VERSION 5.8 ;
BUSBITCHARS "[]" ;
DIVIDERCHAR "/" ;
UNITS
    DATABASE MICRONS 1000 ;
END UNITS

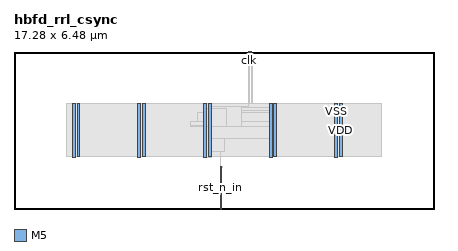
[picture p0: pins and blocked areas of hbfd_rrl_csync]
MACRO hbfd_rrl_csync
  FOREIGN hbfd_rrl_csync 0 0 ;
  CLASS BLOCK ;
  SIZE 17.28 BY 6.48 ;
  PIN clk
    DIRECTION INPUT ;
    USE SIGNAL ;
    PORT
      LAYER M5 ;
        RECT  9.648 6.396 9.672 6.48 ;
    END
  END clk
  PIN rst_n
    DIRECTION OUTPUT ;
    USE SIGNAL ;
    PORT
      LAYER M5 ;
        RECT  9.744 6.396 9.768 6.48 ;
    END
  END rst_n
  PIN rst_n_in
    DIRECTION INPUT ;
    USE SIGNAL ;
    PORT
      LAYER M5 ;
        RECT  8.496 0 8.52 0.084 ;
    END
    PORT
      LAYER M5 ;
        RECT  8.496 0.016 8.52 1.763 ;
    END
  END rst_n_in
  PIN VDD
    DIRECTION INOUT ;
    USE POWER ;
    PORT
      LAYER M5 ;
        RECT  13.392 2.151 13.512 4.329 ;
        RECT  10.692 2.151 10.812 4.329 ;
        RECT  7.992 2.151 8.112 4.329 ;
        RECT  5.292 2.151 5.412 4.329 ;
        RECT  2.592 2.151 2.712 4.329 ;
    END
  END VDD
  PIN VSS
    DIRECTION INOUT ;
    USE GROUND ;
    PORT
      LAYER M5 ;
        RECT  13.2 2.137 13.32 4.343 ;
        RECT  10.5 2.137 10.62 4.343 ;
        RECT  7.8 2.137 7.92 4.343 ;
        RECT  5.1 2.137 5.22 4.343 ;
        RECT  2.4 2.137 2.52 4.343 ;
    END
  END VSS
  # OT_OBS_CLOSED layer=M5 d_um=1.536 added=0
  OBS
    LAYER RVTN ;
     RECT  2.16 2.16 15.12 2.295 ;
     RECT  2.16 2.565 15.12 2.835 ;
     RECT  2.16 3.105 15.12 3.375 ;
     RECT  2.16 3.645 15.12 3.915 ;
     RECT  2.16 4.185 15.12 4.32 ;
    LAYER RVTP ;
     RECT  2.16 2.295 15.12 2.565 ;
     RECT  2.16 2.835 15.12 3.105 ;
     RECT  2.16 3.375 15.12 3.645 ;
     RECT  2.16 3.915 15.12 4.185 ;
    LAYER M1 ;
     RECT  2.16 2.151 15.12 4.329 ;
    LAYER M2 ;
     RECT  2.16 2.151 15.12 4.329 ;
    LAYER M3 ;
     RECT  8.496 1.723 8.514 2.143 ;
     RECT  7.815 2.143 8.514 2.371 ;
     RECT  2.415 2.143 2.505 2.413 ;
     RECT  5.115 2.143 5.205 2.413 ;
     RECT  10.515 2.143 10.605 2.413 ;
     RECT  13.215 2.143 13.305 2.413 ;
     RECT  7.815 2.371 8.658 2.911 ;
     RECT  10.515 2.413 10.797 2.911 ;
     RECT  7.815 2.911 10.797 3.379 ;
     RECT  7.56 3.379 10.797 3.403 ;
     RECT  7.272 3.403 10.797 3.605 ;
     RECT  7.56 3.605 10.797 3.983 ;
     RECT  2.415 2.413 2.697 4.067 ;
     RECT  5.115 2.413 5.397 4.067 ;
     RECT  7.815 3.983 10.797 4.067 ;
     RECT  13.215 2.413 13.497 4.067 ;
     RECT  7.815 4.067 10.605 4.181 ;
     RECT  7.815 4.181 8.406 4.205 ;
     RECT  9.36 4.181 10.605 4.217 ;
     RECT  2.415 4.067 2.505 4.337 ;
     RECT  5.115 4.067 5.205 4.337 ;
     RECT  7.815 4.205 7.905 4.337 ;
     RECT  9.792 4.217 10.605 4.337 ;
     RECT  13.215 4.067 13.305 4.337 ;
     RECT  9.792 4.337 9.81 6.365 ;
    LAYER M4 ;
     RECT  2.408 2.148 2.512 4.332 ;
     RECT  2.512 2.418 2.704 4.062 ;
     RECT  5.108 2.148 5.212 4.332 ;
     RECT  5.212 2.418 5.404 4.062 ;
     RECT  7.261 3.408 7.808 3.432 ;
     RECT  7.808 2.148 7.912 4.332 ;
     RECT  7.912 2.148 8.104 4.2 ;
     RECT  8.485 1.728 8.569 1.752 ;
     RECT  8.104 3.408 9.353 4.2 ;
     RECT  9.733 6.336 9.821 6.36 ;
     RECT  9.353 4.176 10.508 4.2 ;
     RECT  10.508 2.148 10.612 4.332 ;
     RECT  10.612 2.418 10.804 4.062 ;
     RECT  13.208 2.148 13.312 4.332 ;
     RECT  13.312 2.418 13.504 4.062 ;
    LAYER M5 ;
     RECT  2.4 2.137 2.52 2.151 ;
     RECT  5.1 2.137 5.22 2.151 ;
     RECT  10.5 2.137 10.62 2.151 ;
     RECT  13.2 2.137 13.32 2.151 ;
     RECT  7.8 2.137 8.112 3.397 ;
     RECT  7.8 3.397 8.76 4.115 ;
     RECT  10.5 2.151 10.812 4.165 ;
     RECT  2.4 2.151 2.712 4.329 ;
     RECT  5.1 2.151 5.412 4.329 ;
     RECT  7.8 4.115 8.112 4.329 ;
     RECT  9.648 4.165 10.812 4.329 ;
     RECT  13.2 2.151 13.512 4.329 ;
     RECT  2.4 4.329 2.52 4.343 ;
     RECT  5.1 4.329 5.22 4.343 ;
     RECT  7.8 4.329 7.92 4.343 ;
     RECT  9.648 4.329 10.62 4.343 ;
     RECT  13.2 4.329 13.32 4.343 ;
     RECT  9.648 4.343 9.672 6.325 ;
     RECT  9.648 6.325 9.768 6.396 ;
     RECT  9.672 6.396 9.744 6.416 ;
  END
END hbfd_rrl_csync
END LIBRARY
